VERSION 5.8 ;
BUSBITCHARS "[]" ;
DIVIDERCHAR "/" ;
UNITS
    DATABASE MICRONS 1000 ;
END UNITS

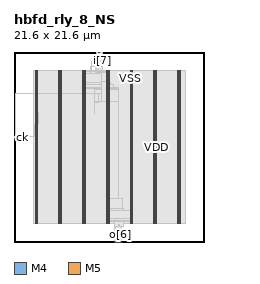
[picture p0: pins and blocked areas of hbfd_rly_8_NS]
MACRO hbfd_rly_8_NS
  FOREIGN hbfd_rly_8_NS 0 0 ;
  CLASS BLOCK ;
  SIZE 21.6 BY 21.6 ;
  PIN ck
    DIRECTION INPUT ;
    USE SIGNAL ;
    PORT
      LAYER M4 ;
        RECT  0 11.856 0.084 11.88 ;
    END
  END ck
  PIN i[0]
    DIRECTION INPUT ;
    USE SIGNAL ;
    PORT
      LAYER M5 ;
        RECT  9.36 21.516 9.384 21.6 ;
    END
  END i[0]
  PIN i[1]
    DIRECTION INPUT ;
    USE SIGNAL ;
    PORT
      LAYER M5 ;
        RECT  9.456 21.516 9.48 21.6 ;
    END
  END i[1]
  PIN i[2]
    DIRECTION INPUT ;
    USE SIGNAL ;
    PORT
      LAYER M5 ;
        RECT  9.552 21.516 9.576 21.6 ;
    END
  END i[2]
  PIN i[3]
    DIRECTION INPUT ;
    USE SIGNAL ;
    PORT
      LAYER M5 ;
        RECT  9.648 21.516 9.672 21.6 ;
    END
  END i[3]
  PIN i[4]
    DIRECTION INPUT ;
    USE SIGNAL ;
    PORT
      LAYER M5 ;
        RECT  9.744 21.516 9.768 21.6 ;
    END
  END i[4]
  PIN i[5]
    DIRECTION INPUT ;
    USE SIGNAL ;
    PORT
      LAYER M5 ;
        RECT  9.84 21.516 9.864 21.6 ;
    END
  END i[5]
  PIN i[6]
    DIRECTION INPUT ;
    USE SIGNAL ;
    PORT
      LAYER M5 ;
        RECT  9.936 21.516 9.96 21.6 ;
    END
  END i[6]
  PIN i[7]
    DIRECTION INPUT ;
    USE SIGNAL ;
    PORT
      LAYER M5 ;
        RECT  10.032 21.516 10.056 21.6 ;
    END
  END i[7]
  PIN o[0]
    DIRECTION OUTPUT ;
    USE SIGNAL ;
    PORT
      LAYER M5 ;
        RECT  11.472 0 11.496 0.084 ;
    END
  END o[0]
  PIN o[1]
    DIRECTION OUTPUT ;
    USE SIGNAL ;
    PORT
      LAYER M5 ;
        RECT  11.568 0 11.592 0.084 ;
    END
  END o[1]
  PIN o[2]
    DIRECTION OUTPUT ;
    USE SIGNAL ;
    PORT
      LAYER M5 ;
        RECT  11.664 0 11.688 0.084 ;
    END
  END o[2]
  PIN o[3]
    DIRECTION OUTPUT ;
    USE SIGNAL ;
    PORT
      LAYER M5 ;
        RECT  11.76 0 11.784 0.084 ;
    END
  END o[3]
  PIN o[4]
    DIRECTION OUTPUT ;
    USE SIGNAL ;
    PORT
      LAYER M5 ;
        RECT  11.856 0 11.88 0.084 ;
    END
  END o[4]
  PIN o[5]
    DIRECTION OUTPUT ;
    USE SIGNAL ;
    PORT
      LAYER M5 ;
        RECT  11.952 0 11.976 0.084 ;
    END
  END o[5]
  PIN o[6]
    DIRECTION OUTPUT ;
    USE SIGNAL ;
    PORT
      LAYER M5 ;
        RECT  12.048 0 12.072 0.084 ;
    END
  END o[6]
  PIN o[7]
    DIRECTION OUTPUT ;
    USE SIGNAL ;
    PORT
      LAYER M5 ;
        RECT  12.144 0 12.168 0.084 ;
    END
  END o[7]
  PIN rs
    DIRECTION INPUT ;
    USE SIGNAL ;
    PORT
      LAYER M4 ;
        RECT  0 11.952 0.084 11.976 ;
    END
  END rs
  PIN VDD
    DIRECTION INOUT ;
    USE POWER ;
    PORT
      LAYER M5 ;
        RECT  18.792 2.151 18.912 19.449 ;
        RECT  16.092 2.151 16.212 19.449 ;
        RECT  13.392 2.151 13.512 19.449 ;
        RECT  10.692 2.151 10.812 19.449 ;
        RECT  7.992 2.151 8.112 19.449 ;
        RECT  5.292 2.151 5.412 19.449 ;
        RECT  2.592 2.151 2.712 19.449 ;
    END
  END VDD
  PIN VSS
    DIRECTION INOUT ;
    USE GROUND ;
    PORT
      LAYER M5 ;
        RECT  18.6 2.137 18.72 19.463 ;
        RECT  15.9 2.137 16.02 19.463 ;
        RECT  13.2 2.137 13.32 19.463 ;
        RECT  10.5 2.137 10.62 19.463 ;
        RECT  7.8 2.137 7.92 19.463 ;
        RECT  5.1 2.137 5.22 19.463 ;
        RECT  2.4 2.137 2.52 19.463 ;
    END
  END VSS
  # OT_OBS_CLOSED layer=M5 d_um=1.536 added=5
  OBS
    LAYER RVTN ;
     RECT  2.16 2.16 19.44 2.295 ;
     RECT  2.16 2.565 19.44 2.835 ;
     RECT  2.16 3.105 19.44 3.375 ;
     RECT  2.16 3.645 19.44 3.915 ;
     RECT  2.16 4.185 19.44 4.455 ;
     RECT  2.16 4.725 19.44 4.995 ;
     RECT  2.16 5.265 19.44 5.535 ;
     RECT  2.16 5.805 19.44 6.075 ;
     RECT  2.16 6.345 19.44 6.615 ;
     RECT  2.16 6.885 19.44 7.155 ;
     RECT  2.16 7.425 19.44 7.695 ;
     RECT  2.16 7.965 19.44 8.235 ;
     RECT  2.16 8.505 19.44 8.775 ;
     RECT  2.16 9.045 19.44 9.315 ;
     RECT  2.16 9.585 19.44 9.855 ;
     RECT  2.16 10.125 19.44 10.395 ;
     RECT  2.16 10.665 19.44 10.935 ;
     RECT  2.16 11.205 19.44 11.475 ;
     RECT  2.16 11.745 19.44 12.015 ;
     RECT  2.16 12.285 19.44 12.555 ;
     RECT  2.16 12.825 19.44 13.095 ;
     RECT  2.16 13.365 19.44 13.635 ;
     RECT  2.16 13.905 19.44 14.175 ;
     RECT  2.16 14.445 19.44 14.715 ;
     RECT  2.16 14.985 19.44 15.255 ;
     RECT  2.16 15.525 19.44 15.795 ;
     RECT  2.16 16.065 19.44 16.335 ;
     RECT  2.16 16.605 19.44 16.875 ;
     RECT  2.16 17.145 19.44 17.415 ;
     RECT  2.16 17.685 19.44 17.955 ;
     RECT  2.16 18.225 19.44 18.495 ;
     RECT  2.16 18.765 19.44 19.035 ;
     RECT  2.16 19.305 19.44 19.44 ;
    LAYER RVTP ;
     RECT  2.16 2.295 19.44 2.565 ;
     RECT  2.16 2.835 19.44 3.105 ;
     RECT  2.16 3.375 19.44 3.645 ;
     RECT  2.16 3.915 19.44 4.185 ;
     RECT  2.16 4.455 19.44 4.725 ;
     RECT  2.16 4.995 19.44 5.265 ;
     RECT  2.16 5.535 19.44 5.805 ;
     RECT  2.16 6.075 19.44 6.345 ;
     RECT  2.16 6.615 19.44 6.885 ;
     RECT  2.16 7.155 19.44 7.425 ;
     RECT  2.16 7.695 19.44 7.965 ;
     RECT  2.16 8.235 19.44 8.505 ;
     RECT  2.16 8.775 19.44 9.045 ;
     RECT  2.16 9.315 19.44 9.585 ;
     RECT  2.16 9.855 19.44 10.125 ;
     RECT  2.16 10.395 19.44 10.665 ;
     RECT  2.16 10.935 19.44 11.205 ;
     RECT  2.16 11.475 19.44 11.745 ;
     RECT  2.16 12.015 19.44 12.285 ;
     RECT  2.16 12.555 19.44 12.825 ;
     RECT  2.16 13.095 19.44 13.365 ;
     RECT  2.16 13.635 19.44 13.905 ;
     RECT  2.16 14.175 19.44 14.445 ;
     RECT  2.16 14.715 19.44 14.985 ;
     RECT  2.16 15.255 19.44 15.525 ;
     RECT  2.16 15.795 19.44 16.065 ;
     RECT  2.16 16.335 19.44 16.605 ;
     RECT  2.16 16.875 19.44 17.145 ;
     RECT  2.16 17.415 19.44 17.685 ;
     RECT  2.16 17.955 19.44 18.225 ;
     RECT  2.16 18.495 19.44 18.765 ;
     RECT  2.16 19.035 19.44 19.305 ;
    LAYER M1 ;
     RECT  2.16 2.151 19.44 19.449 ;
    LAYER M2 ;
     RECT  2.16 2.151 19.44 19.449 ;
    LAYER M3 ;
     RECT  11.772 0.091 11.79 0.571 ;
     RECT  11.448 0.571 12.258 1.723 ;
     RECT  10.515 2.143 10.605 2.335 ;
     RECT  11.448 1.723 12.438 2.335 ;
     RECT  10.515 2.335 12.438 2.371 ;
     RECT  13.215 2.143 13.305 2.371 ;
     RECT  2.415 2.143 2.505 2.413 ;
     RECT  5.115 2.143 5.205 2.413 ;
     RECT  7.815 2.143 7.905 2.413 ;
     RECT  10.515 2.371 13.305 2.413 ;
     RECT  15.915 2.143 16.005 2.413 ;
     RECT  18.615 2.143 18.705 2.413 ;
     RECT  10.515 2.413 13.497 2.641 ;
     RECT  10.476 2.641 13.497 3.569 ;
     RECT  10.476 3.569 12.474 3.839 ;
     RECT  10.476 3.839 12.366 4.919 ;
     RECT  2.415 2.413 2.697 11.947 ;
     RECT  2.304 11.947 2.697 13.325 ;
     RECT  2.415 13.325 2.697 13.441 ;
     RECT  2.415 13.441 2.826 14.675 ;
     RECT  9.144 14.611 9.162 15.835 ;
     RECT  9.144 15.835 9.666 15.871 ;
     RECT  9.144 15.871 9.738 15.997 ;
     RECT  10.476 4.919 11.934 15.997 ;
     RECT  9.144 15.997 11.934 17.339 ;
     RECT  7.815 2.413 8.097 17.455 ;
     RECT  9.144 17.339 11.862 17.455 ;
     RECT  7.815 17.455 11.862 17.609 ;
     RECT  7.815 17.609 11.358 17.879 ;
     RECT  7.815 17.879 10.998 18.149 ;
     RECT  2.415 14.675 2.697 19.187 ;
     RECT  5.115 2.413 5.397 19.187 ;
     RECT  7.815 18.149 10.797 19.187 ;
     RECT  13.215 3.569 13.497 19.187 ;
     RECT  15.915 2.413 16.197 19.187 ;
     RECT  18.615 2.413 18.897 19.187 ;
     RECT  8.712 19.187 10.605 19.373 ;
     RECT  9.612 19.373 9.774 19.379 ;
     RECT  2.415 19.187 2.505 19.457 ;
     RECT  5.115 19.187 5.205 19.457 ;
     RECT  7.815 19.187 7.905 19.457 ;
     RECT  10.515 19.373 10.605 19.457 ;
     RECT  13.215 19.187 13.305 19.457 ;
     RECT  15.915 19.187 16.005 19.457 ;
     RECT  18.615 19.187 18.705 19.457 ;
     RECT  8.712 19.373 8.838 19.997 ;
     RECT  9.612 19.379 9.63 20.525 ;
     RECT  8.82 19.997 8.838 20.573 ;
    LAYER M4 ;
     RECT  0.06 11.856 0.227 11.976 ;
     RECT  0.227 11.952 2.408 11.976 ;
     RECT  0.181 16.896 2.408 16.92 ;
     RECT  2.408 2.148 2.512 19.452 ;
     RECT  2.512 2.418 2.704 19.182 ;
     RECT  2.704 16.896 5.108 16.92 ;
     RECT  5.108 2.148 5.212 19.452 ;
     RECT  5.212 2.418 5.404 19.182 ;
     RECT  5.404 16.896 7.808 16.92 ;
     RECT  7.808 2.148 7.912 19.452 ;
     RECT  7.912 2.418 8.104 19.452 ;
     RECT  8.701 19.968 8.809 19.992 ;
     RECT  8.809 19.968 9.313 20.568 ;
     RECT  9.313 19.296 9.395 20.568 ;
     RECT  9.395 19.296 9.491 20.52 ;
     RECT  8.104 16.896 9.637 16.92 ;
     RECT  9.491 20.496 9.875 20.52 ;
     RECT  9.637 15.936 9.932 16.92 ;
     RECT  9.421 18.144 9.973 18.168 ;
     RECT  9.932 15.936 10.508 17.112 ;
     RECT  9.973 18.144 10.508 18.264 ;
     RECT  9.491 19.296 10.508 19.368 ;
     RECT  10.508 2.148 10.612 19.452 ;
     RECT  10.612 2.148 10.804 19.182 ;
     RECT  11.437 0.576 11.717 0.6 ;
     RECT  11.717 0.096 11.801 0.6 ;
     RECT  11.557 1.728 11.825 1.8 ;
     RECT  11.825 1.728 11.908 1.896 ;
     RECT  11.908 1.728 12.025 1.944 ;
     RECT  11.801 0.576 12.269 0.6 ;
     RECT  12.025 1.728 12.449 1.752 ;
     RECT  13.208 2.148 13.312 19.452 ;
     RECT  13.312 2.418 13.504 19.182 ;
     RECT  15.908 2.148 16.012 19.452 ;
     RECT  16.012 2.418 16.204 19.182 ;
     RECT  18.608 2.148 18.712 19.452 ;
     RECT  18.712 2.418 18.904 19.182 ;
    LAYER M5 ;
     RECT  11.472 0.016 12.168 0.611 ;
     RECT  11.568 0.611 12.168 1.763 ;
     RECT  11.568 1.763 11.976 1.811 ;
     RECT  11.856 1.811 11.976 1.907 ;
     RECT  11.952 1.907 11.976 1.955 ;
     RECT  2.4 2.137 2.52 2.151 ;
     RECT  5.1 2.137 5.22 2.151 ;
     RECT  7.8 2.137 7.92 2.151 ;
     RECT  13.2 2.137 13.32 2.151 ;
     RECT  15.9 2.137 16.02 2.151 ;
     RECT  18.6 2.137 18.72 2.151 ;
     RECT  10.5 2.137 10.812 15.925 ;
     RECT  0.192 11.845 0.216 16.931 ;
     RECT  9.984 15.925 10.812 18.275 ;
     RECT  10.5 18.275 10.812 19.285 ;
     RECT  9.648 19.285 10.812 19.333 ;
     RECT  2.4 2.151 2.712 19.449 ;
     RECT  5.1 2.151 5.412 19.449 ;
     RECT  7.8 2.151 8.112 19.449 ;
     RECT  9.552 19.333 10.812 19.449 ;
     RECT  13.2 2.151 13.512 19.449 ;
     RECT  15.9 2.151 16.212 19.449 ;
     RECT  18.6 2.151 18.912 19.449 ;
     RECT  2.4 19.449 2.52 19.463 ;
     RECT  5.1 19.449 5.22 19.463 ;
     RECT  7.8 19.449 7.92 19.463 ;
     RECT  9.552 19.449 10.62 19.463 ;
     RECT  13.2 19.449 13.32 19.463 ;
     RECT  15.9 19.449 16.02 19.463 ;
     RECT  18.6 19.449 18.72 19.463 ;
     RECT  9.552 19.463 10.056 19.957 ;
     RECT  9.456 19.957 10.056 20.533 ;
     RECT  9.36 20.533 10.056 21.584 ;
     RECT  9.984 18.275 10.5 19.285 ;
     RECT  8.112 19.333 9.552 19.449 ;
     RECT  7.92 19.449 9.552 19.463 ;
     RECT  9.36 19.463 9.552 19.957 ;
     RECT  9.36 19.957 9.456 20.533 ;
  END
END hbfd_rly_8_NS
END LIBRARY
